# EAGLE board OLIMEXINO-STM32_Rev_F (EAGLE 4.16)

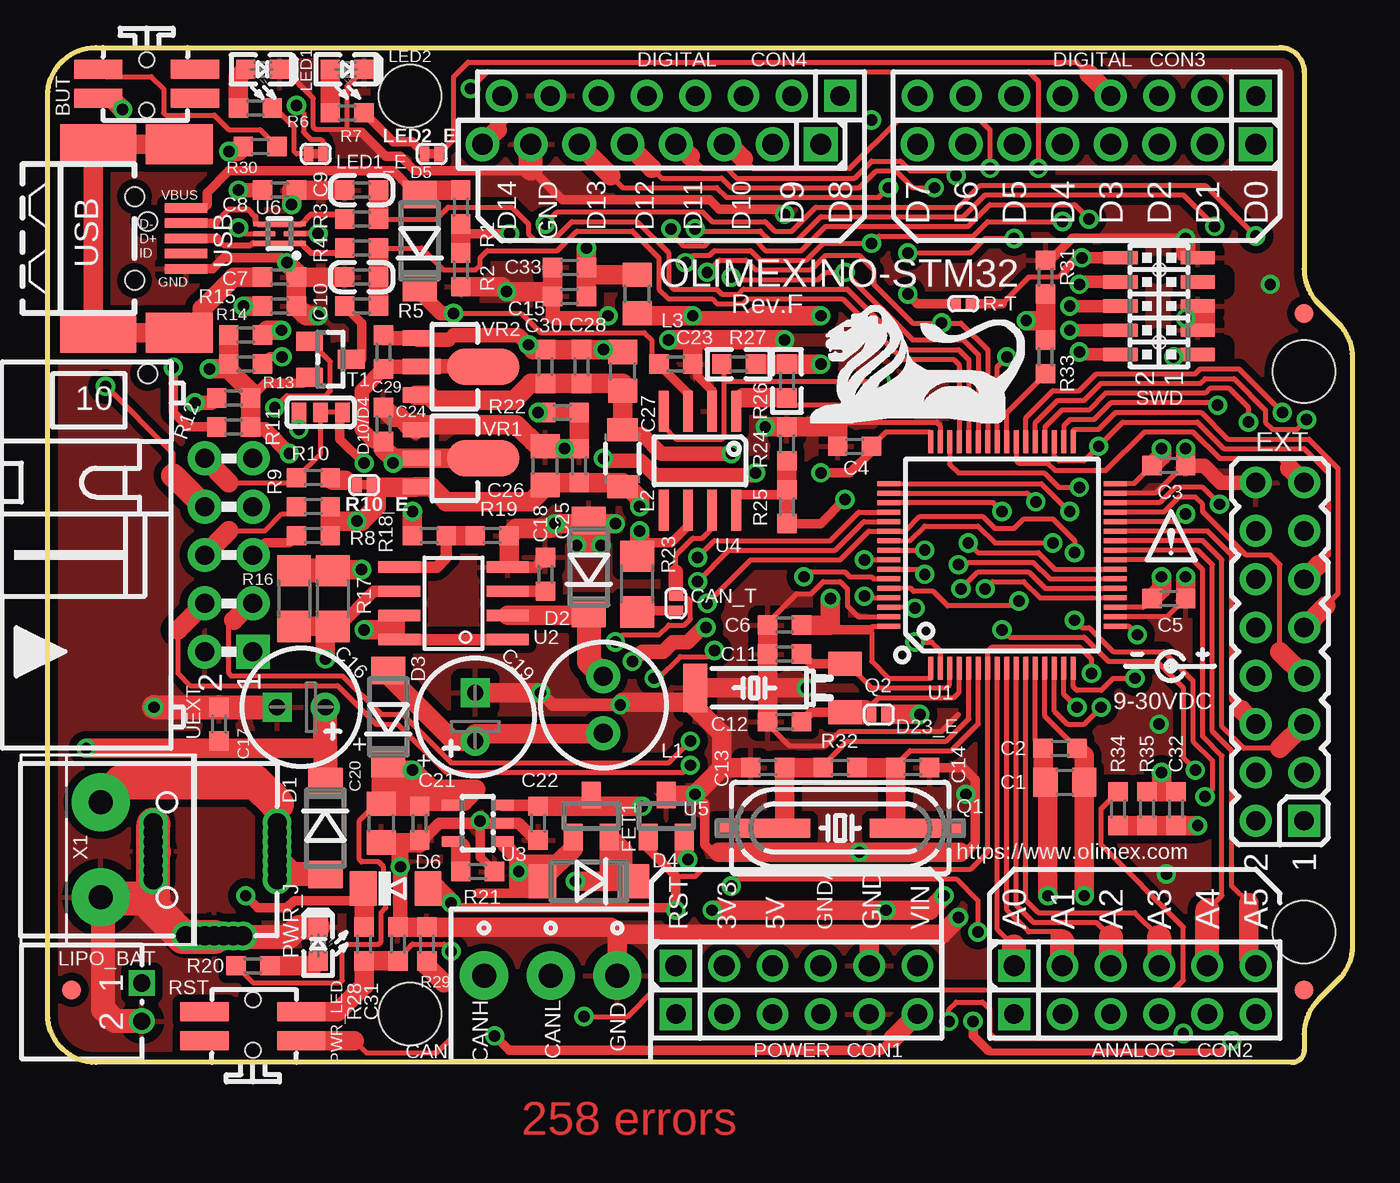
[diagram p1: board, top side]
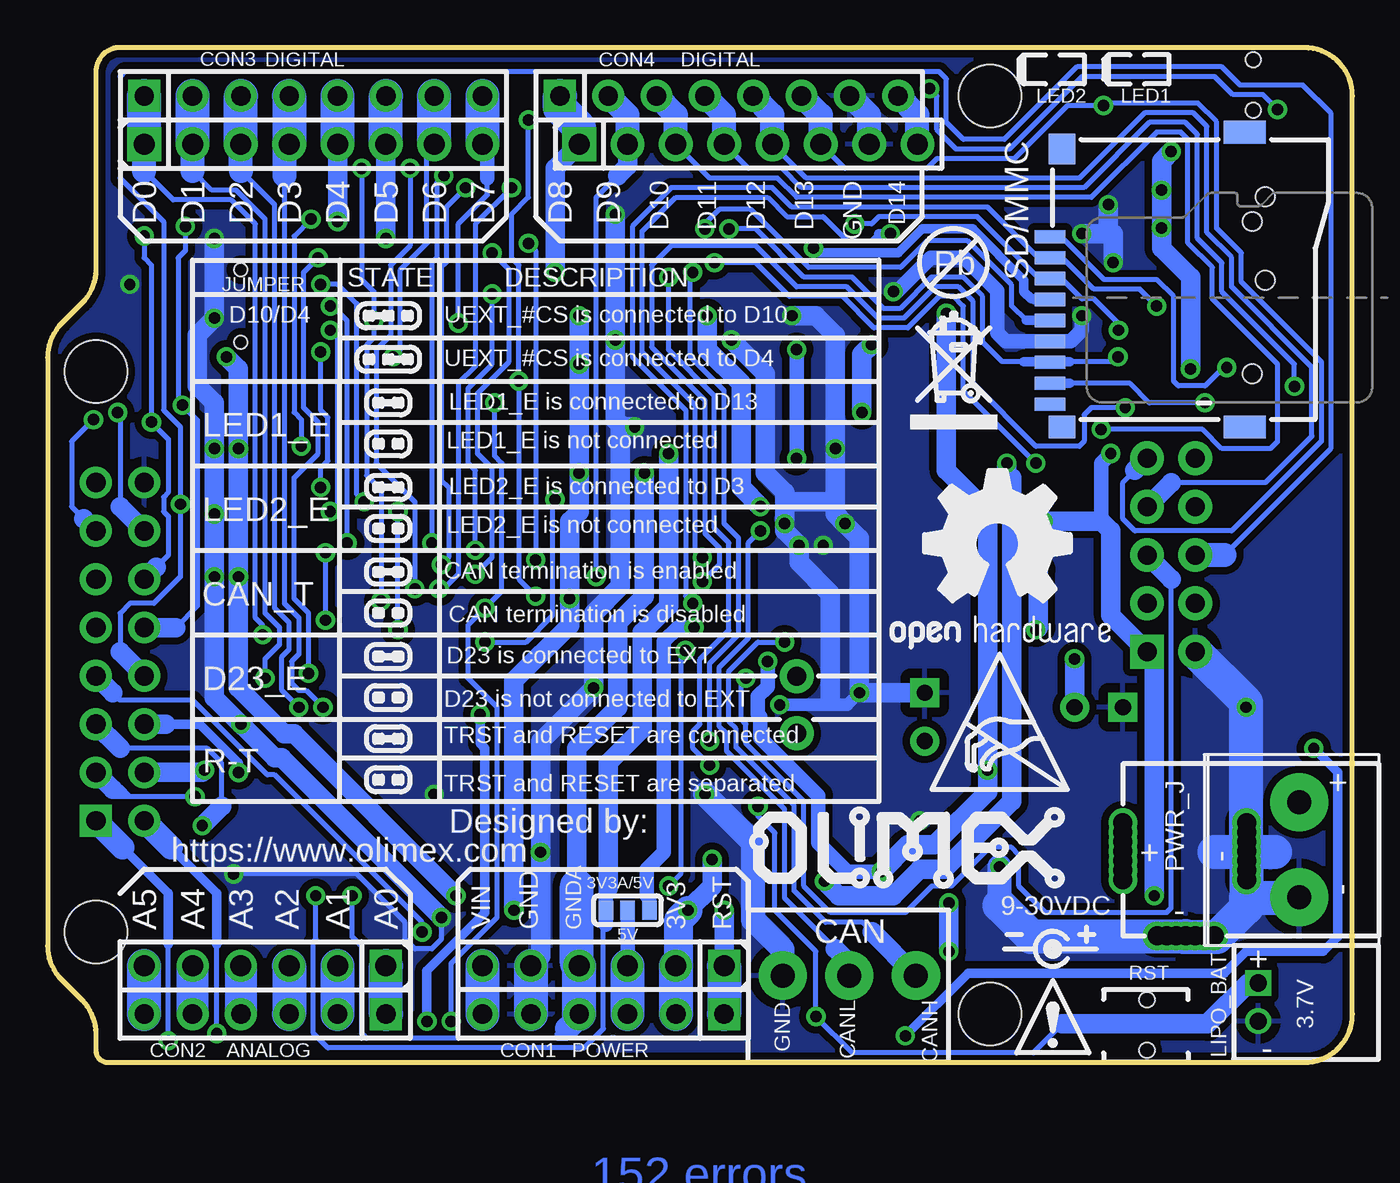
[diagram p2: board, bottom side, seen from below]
Size 68.58 x 53.34 mm. Coordinates in mm from the lower left corner, seen from the top.
Copper layers (1+16): Top 0.035mm / dielectric 1.5mm / Bottom 0.035mm
Design rules "default": minimum track width 10mil, minimum drill 0.6mm, track to track 9.5mil, track to pad 9.5mil, pad to pad 9.5mil, via to via 9.5mil, smd to smd 1mil, copper to edge 10mil, drill to drill 8mil, minimum pad ring 8mil, minimum via ring 8mil, stop-mask expansion 4mil, vias tented up to drill 25mil, thermal gap 20mil
Net classes: 0 default: width 0.241 mm, drill 0.241 mm, clearance 0.584 mm; 1 pwr: width 0.25 mm
tRestrict: 2 lines

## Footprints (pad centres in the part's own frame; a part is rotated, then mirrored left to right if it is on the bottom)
SJ_2_SMALL = smd 0.762 x 1.016: 1 -1.143,0; 2 0,0; 3 1.143,0
SW_TAKT3X4 = smd 2.54 x 1.016: 1_1 2.54,-0.762; 1_2 -2.54,-0.762; 2_1 2.54,0.762; 2_2 -2.54,0.762 | hole 0.8: 0,1.397; 0,-1.27
C0805_5MIL_DWS = smd 1.27 x 1.524: 1 -1.016,0; 2 1.016,0
C0603_DWS = smd 1.016 x 1.016: 1 -0.889,0; 2 0.889,0
C0603_DWS_NA = smd 1.016 x 1.016: 1 -0.889,0; 2 0.889,0
E2,5-6,3 = drill 0.864 pad 1.524 round: + -1.27,0 | drill 0.864 pad 1.524 square: - 1.27,0
CON3/3.5MM = drill 1.27 pad 2.54 round: 1 -1.75,-0.5; 2 1.75,-0.5; 3 5.25,-0.5
SJ_1_SMALLER = smd 0.508 x 0.762: 1 -0.381,0; 2 0.381,0
PN1X6 = drill 1.1 pad 1.676 square: 1 -6.35,0 | drill 1.1 pad 1.676 round: 2 -3.81,0; 3 -1.27,0; 4 1.27,0; 5 3.81,0; 6 6.35,0
PN1X8 = drill 1.1 pad 1.778 square: 1 -8.89,0 | drill 1.1 pad 1.778 round: 2 -6.35,0; 3 -3.81,0; 4 -1.27,0; 5 1.27,0; 6 3.81,0; 7 6.35,0; 8 8.89,0
MLL-41 = smd 1.45 x 1.8: A 2.445,0; K -2.445,0
MINI-MELF = smd 1.4 x 1.8: A 1.7,0; C -1.7,0
HN2X8-MALE = drill 1.016 pad 1.676 square: 1 -8.89,-1.27 | drill 1.016 pad 1.676 round: 2 -8.89,1.27; 3 -6.35,-1.27; 4 -6.35,1.27; 5 -3.81,-1.27; 6 -3.81,1.27; 7 -1.27,-1.27; 8 -1.27,1.27; 9 1.27,-1.27; 10 1.27,1.27; 11 3.81,-1.27; 12 3.81,1.27; 13 6.35,-1.27; 14 6.35,1.27; 15 8.89,-1.27; 16 8.89,1.27
SOT23 = smd 1.4 x 1: 1 1.1,-0.95; 2 1.1,0.95; 3 -1.1,0
SW68 = drill 1 pad 1.778 round: 1 -1.5,0; 2 1.5,0
L3216C = smd 1.2 x 1.6: 1 -1.5,0; 2 1.5,0
L0805_5MIL_DWS = smd 1.27 x 1.524: 1 -1.016,0; 2 1.016,0
LED-0603 = smd 1.016 x 1.016: A 0.889,0; C -0.889,0
SJ_1_SMALLER_CLOSE = smd 0.508 x 0.762: 1 -0.381,0; 2 0.381,0
DW02R = drill 0.9 square: 1 -1,0 | drill 0.9 round: 2 1,0
PWR_JACK_UNI_MILLING = drill 1 round: + 0,4.75; +1 0,5.25; +2 0,5.75; +3 0,6.25; +4 0,4.25; +5 0,3.75; +6 0,3.25; - -6.5,4.75; -1 -6.5,5.25; -2 -6.5,5.75; -3 -6.5,4.25; -4 -6.5,3.75; -5 -6.5,6.25; -6 -6.5,3.25; -- -3.3,0.3; --1 -3.8,0.3; --2 -4.3,0.3; --3 -4.8,0.3; --4 -2.8,0.3; --5 -2.3,0.3; --6 -1.8,0.3
HC49/SMD2_THIN = smd 5 x 1: 1 -4.064,0; 2 4.064,0
TC26H_3_REPAIR_SMD = smd 1.27 x 1.778: 1 -1.27,0; 2 1.27,0 | smd 2.54 x 1.27: GND 0,7.874
R0603_5MIL_DWS = smd 1.016 x 1.016: 1 -0.889,0; 2 0.889,0
R1206_5MIL_WS = smd 1.651 x 1.778: 1 -1.46,0; 2 1.46,0
0603_0R = smd 1.016 x 1.016: 1 -0.889,0; 2 0.889,0
R0603_5MIL_DWS_NA = smd 1.016 x 1.016: 1 -0.889,0; 2 0.889,0
SJ_1_THE_SMALLEST = smd 0.508 x 0.508: 1 -0.381,0; 2 0.381,0
TFC-WPAPR-08 = smd 1.6 x 0.7: 1 -7.375,2.25; 2 -7.375,1.15; 3 -7.375,0.05; 4 -7.375,-1.05; 5 -7.375,-2.15; 6 -7.375,-3.25; 7 -7.375,-4.35; 8 -7.375,-5.45; 9 -7.375,-6.55 | smd 1.4 x 1.2: 10 -6.75,-7.75 | smd 1.4 x 1.6: 11 -6.75,6.85 | smd 2.2 x 1.2: 12 2.85,-7.75; 13 2.85,7.75 | hole 1: 3.25,-4.95; 3.25,3.05
GPH127SMT-02X05(PA-V16X-2X5-LF) = smd 0.7 x 1.8: 1 -2.54,-2.032; 2 -2.54,2.032; 3 -1.27,-2.032; 4 -1.27,2.032; 5 0,-2.032; 6 0,2.032; 7 1.27,-2.032; 8 1.27,2.032; 9 2.54,-2.032; 10 2.54,2.032 | hole 0.7: -1.905,0; 1.905,0
SOT-23 = smd 1.4 x 1: 1 1.1,-0.95; 2 1.1,0.95; 3 -1.1,0
LPTQFP64 = smd 0.254 x 1.2: 1 -3.75,-5.95; 2 -3.25,-5.95; 3 -2.75,-5.95; 4 -2.25,-5.95; 5 -1.75,-5.95; 6 -1.25,-5.95; 7 -0.75,-5.95; 8 -0.25,-5.95; 9 0.25,-5.95; 10 0.75,-5.95; 11 1.25,-5.95; 12 1.75,-5.95; 13 2.25,-5.95; 14 2.75,-5.95; 15 3.25,-5.95; 16 3.75,-5.95; 33 3.75,5.95; 34 3.25,5.95; 35 2.75,5.95; 36 2.25,5.95; 37 1.75,5.95; 38 1.25,5.95; 39 0.75,5.95; 40 0.25,5.95; 41 -0.25,5.95; 42 -0.75,5.95; 43 -1.25,5.95; 44 -1.75,5.95; 45 -2.25,5.95; 46 -2.75,5.95; 47 -3.25,5.95; 48 -3.75,5.95 | smd 1.2 x 0.254: 17 5.95,-3.75; 18 5.95,-3.25; 19 5.95,-2.75; 20 5.95,-2.25; 21 5.95,-1.75; 22 5.95,-1.25; 23 5.95,-0.75; 24 5.95,-0.25; 25 5.95,0.25; 26 5.95,0.75; 27 5.95,1.25; 28 5.95,1.75; 29 5.95,2.25; 30 5.95,2.75; 31 5.95,3.25; 32 5.95,3.75; 49 -5.95,3.75; 50 -5.95,3.25; 51 -5.95,2.75; 52 -5.95,2.25; 53 -5.95,1.75; 54 -5.95,1.25; 55 -5.95,0.75; 56 -5.95,0.25; 57 -5.95,-0.25; 58 -5.95,-0.75; 59 -5.95,-1.25; 60 -5.95,-1.75; 61 -5.95,-2.25; 62 -5.95,-2.75; 63 -5.95,-3.25; 64 -5.95,-3.75
SO-8 = smd 0.6 x 2.2: 1 -1.905,-2.854; 2 -0.635,-2.854; 3 0.635,-2.854; 4 1.905,-2.854; 5 1.905,2.854; 6 0.635,2.854; 7 -0.635,2.854; 8 -1.905,2.854
SOT-23-5 = smd 1.2 x 0.55: 1 1.3,-0.95; 2 1.3,0; 3 1.3,0.95; 4 -1.3,0.95; 5 -1.3,-0.95
SO-08_THIN = smd 0.508 x 2.159: 1 -1.905,-2.603; 2 -0.635,-2.603; 3 0.635,-2.603; 4 1.905,-2.603; 5 1.905,2.603; 6 0.635,2.603; 7 -0.635,2.603; 8 -1.905,2.603
USBLC6-2P6 = smd 1.46 x 0.25: 1 0.65,-0.5; 3 0.65,0.5; 4 -0.65,0.5; 6 -0.65,-0.5 | smd 1.16 x 0.25: 2 0.8,0; 5 -0.8,0
FIDUCIAL-1X2 = smd 1 x 1: 1 0,0
STM32-MAPLE_PATFORM-CON1-PIN3_5V = drill 1.016 pad 1.676 round: 3V3 35.56,2.54; 5V 38.1,2.54; A1 53.34,2.54; A2 55.88,2.54; A3 58.42,2.54; A4 60.96,2.54; A5 63.5,2.54; D1 60.96,50.8; D2 58.42,50.8; D3 55.88,50.8; D4 53.34,50.8; D5 50.8,50.8; D6 48.26,50.8; D7 45.72,50.8; D9 39.116,50.8; D10 36.576,50.8; D11 34.036,50.8; D12 31.496,50.8; D13 28.956,50.8; D14 23.876,50.8; GND 43.18,2.54; GND@1 26.416,50.8; GNDA 40.64,2.54; VIN 45.72,2.54 | drill 1.016 pad 1.676 square: A0 50.8,2.54; D0 63.5,50.8; D8 41.656,50.8; RST 33.02,2.54 | hole 3.3: 66.04,36.322; 66.04,6.858; 19.05,50.8; 19.05,2.54
BH10R = drill 1 pad 1.778 square: 1 -5.08,-1.27 | drill 1 pad 1.778 round: 2 -5.08,1.27; 3 -2.54,-1.27; 4 -2.54,1.27; 5 0,-1.27; 6 0,1.27; 7 2.54,-1.27; 8 2.54,1.27; 9 5.08,-1.27; 10 5.08,1.27
USB_MINI_9PIN-SMALLER_CREAM = smd 2.25 x 0.5: D+ -5.246,0; D- -5.246,-0.8; GND -5.246,1.6; ID -5.246,0.8; VBUS -5.246,-1.6 | smd 4 x 2.1: GND1 -0.64,-4.95; GND3 -0.64,4.95 | smd 3.5 x 2.1: GND2 -4.89,-4.95; GND4 -4.89,4.95 | hole 1: -2.54,-2.2; -2.54,2.2
SOT89_REP_THERMALOFF = smd 1.4 x 0.8: 1 1.981,-1.499; 3 1.981,1.499 | smd 2 x 0.8: 2 1.681,0 | smd 3.81 x 1.93: P$2 -1.57,0
W237-102 = drill 1.27 pad 3.048 round: 1 -2.5,-1.27; 2 2.5,-1.27

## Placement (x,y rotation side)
3V3A/5V  5V_default  [SJ_2_SMALL]  38.1,8 0 bottom
BUT  SW-SIDE_WTCM-TR(3X4)  [SW_TAKT3X4]  5.21,51.44 180 top
C1  10uF/6.3V  [C0805_5MIL_DWS]  53.47,14.73 0 top
C2  100nF  [C0603_DWS]  53.21,16.51 0 top
C3  100nF  [C0603_DWS]  58.93,31.37 180 top
C4  100nF  [C0603_DWS]  42.42,32.38 0 top
C5  100nF  [C0603_DWS]  58.93,24.38 180 top
C6  4.7uF/6.3V  [C0603_DWS]  38.73,22.99 0 top
C7  10nF  [C0603_DWS]  12.19,41.27 0 top
C8  100nF  [C0603_DWS]  12.19,45.85 180 top
C9  NA(47pF)  [C0603_DWS_NA]  16.51,45.85 180 top
C10  NA(47pF)  [C0603_DWS_NA]  16.51,41.27 180 top
C11  10pF  [C0603_DWS]  38.73,21.46 180 top
C12  10pF  [C0603_DWS]  38.73,17.91 180 top
C13  27pF  [C0603_DWS]  37.85,15.49 180 top
C14  27pF  [C0603_DWS]  45.47,15.49 0 top
C15  22uF/6.3V  [C0603_DWS]  27.43,40.26 180 top
C16  CE 100uF/35V/6.3x11mm/RM2.5  [E2,5-6,3]  13.34,18.67 180 top
C17  100nF  [C0603_DWS]  9.02,17.78 90 top
C18  820pF  [C0603_DWS]  26.16,25.65 90 top
C19  CE 470uF/10V/6.3x11mm/RM2.5  [E2,5-6,3]  22.48,18.16 90 top
C20  10uF/6.3V  [C0805_5MIL_DWS]  17.53,12.57 270 top
C21  2.2uF  [C0603_DWS]  19.56,12.57 270 top
C22  2.2uF  [C0603_DWS]  25.78,12.57 270 top
C23  100nF  [C0603_DWS]  33.02,36.7 0 top
C24  2.2uF  [C0603_DWS]  17.65,33.53 90 top
C25  100nF  [C0603_DWS]  27.94,31.37 90 top
C26  10uF/6.3V  [C0805_5MIL_DWS]  26.16,31.37 90 top
C27  10uF/6.3V  [C0805_5MIL_DWS]  30.23,36.32 90 top
C28  10nF  [C0603_DWS]  28.07,36.58 90 top
C29  2.2uF  [C0603_DWS]  17.65,37.34 90 top
C30  2.2uF  [C0603_DWS]  26.16,36.58 90 top
C31  100nF  [C0603_DWS]  18.41,6.22 90 top
C32  10nF  [C0603_DWS]  59.31,13.34 270 top
C33  22uF/6.3V  [C0603_DWS]  27.43,41.78 180 top
CAN  TB3-3.5MM  [CON3/3.5MM]  28.19,4.06 180 top
CAN_T  Open  [SJ_1_SMALLER]  33.02,24.13 90 top
CON1  NA  [PN1X6]  39.37,5.08 0 top
CON2  NA  [PN1X6]  57.15,5.08 0 top
CON3  NA  [PN1X8]  54.61,48.26 180 top
CON4  NA  [PN1X8]  31.75,48.26 180 top
D1  1N5819S/SS14  [MLL-41]  14.61,12.32 270 top
D2  1N5819S/SS14  [MLL-41]  28.45,26.04 90 top
D3  1N5819S/SS14  [MLL-41]  17.91,18.16 90 top
D4  1N5819S/SS14  [MLL-41]  28.45,9.53 180 top
D5  1N5819S/SS14  [MLL-41]  19.56,43.18 90 top
D6  1N4148/mini-melf  [MINI-MELF]  18.29,9.14 0 top
D10/D4  D10:Open/D4:Close  [SJ_2_SMALL]  14.35,34.16 180 top
D23_E  Open  [SJ_1_SMALLER]  43.69,18.29 0 top
EXT  PN2x8  [HN2X8-MALE]  64.77,21.59 90 top
FET1  IRLML6402  [SOT23]  28.57,12.95 270 top
L1  CL10uH SW68  [SW68]  29.21,18.8 270 top
L2  NA  [L3216C]  30.23,31.75 90 top
L3  CL470nH/0805/1.76R/250mA  [L0805_5MIL_DWS]  30.99,40.39 90 top
LED1  GREEN(0603)  [LED-0603]  11.3,52.2 180 top
LED1_E  Close  [SJ_1_SMALLER_CLOSE]  14.1,47.75 0 top
LED2  YELLOW(0603)  [LED-0603]  15.75,52.2 180 top
LED2_E  Close  [SJ_1_SMALLER_CLOSE]  20.19,47.75 0 top
LIPO_BAT  DW02R  [DW02R]  4.95,3.17 270 top
PWR_J  YDJ-1136  [PWR_JACK_UNI_MILLING]  12.06,6.35 0 top
PWR_LED  RED(0603)  [LED-0603]  14.22,6.22 270 top
Q1  HC49/S1  [HC49/SMD2_THIN]  41.66,12.32 180 top
Q2  32768Hz/6pF  [TC26H_3_REPAIR_SMD]  41.91,19.68 90 top
R1  15k  [R0603_5MIL_DWS]  21.72,44.96 270 top
R2  22k  [R0603_5MIL_DWS]  21.72,41.66 270 top
R3  22R  [R0603_5MIL_DWS]  16.51,44.32 180 top
R4  22R  [R0603_5MIL_DWS]  16.51,42.8 180 top
R5  1.5k  [R0603_5MIL_DWS]  16.51,39.75 180 top
R6  2k  [R0603_5MIL_DWS]  10.92,50.16 0 top
R7  2k  [R0603_5MIL_DWS]  15.75,49.91 0 top
R8  4.7k  [R0603_5MIL_DWS]  13.97,27.69 0 top
R9  4.7k  [R0603_5MIL_DWS]  13.97,29.21 0 top
R10  10k  [R0603_5MIL_DWS]  13.97,30.73 0 top
R10_E  Close  [SJ_1_SMALLER_CLOSE]  16.64,30.35 0 top
R11  100k  [R0603_5MIL_DWS]  9.78,33.4 180 top
R12  100k  [R0603_5MIL_DWS]  9.78,34.92 180 top
R13  100k  [R0603_5MIL_DWS]  10.41,36.7 0 top
R14  10k  [R0603_5MIL_DWS]  10.41,38.23 0 top
R15  1M  [R0603_5MIL_DWS]  12.19,39.75 180 top
R16  0.47R  [R1206_5MIL_WS]  12.95,24.38 90 top
R17  0.47R  [R1206_5MIL_WS]  14.99,24.38 90 top
R18  3.01k/1%  [R0603_5MIL_DWS]  20.07,27.69 0 top
R19  1k/1%  [R0603_5MIL_DWS]  23.37,27.69 0 top
R20  2k  [R0603_5MIL_DWS]  10.79,5.08 0 top
R21  15k  [R0603_5MIL_DWS]  22.61,10.03 180 top
R22  0R(boad mounted)  [0603_0R]  27.05,34.16 180 top
R23  120R  [R1206_5MIL_WS]  30.99,25.15 270 top
R24  10k  [R0603_5MIL_DWS]  38.86,32.51 270 top
R25  0R(boad mounted)  [0603_0R]  38.86,29.21 90 top
R26  NA(4.7k)  [R0603_5MIL_DWS_NA]  38.86,35.81 270 top
R27  NA(4.7k)  [R0603_5MIL_DWS_NA]  36.32,36.7 180 top
R28  10k  [R0603_5MIL_DWS]  16.64,6.22 270 top
R29  330R  [R0603_5MIL_DWS]  19.94,6.22 270 top
R30  1k  [R0603_5MIL_DWS]  11.18,48.13 0 top
R31  10k  [R0603_5MIL_DWS]  52.45,41.27 90 top
R32  1M  [R0603_5MIL_DWS]  41.66,15.49 180 top
R33  1k  [R0603_5MIL_DWS]  52.45,37.08 270 top
R34  3M  [R0603_5MIL_DWS]  56.26,13.34 90 top
R35  1M  [R0603_5MIL_DWS]  57.78,13.34 90 top
R-T  Open  [SJ_1_THE_SMALLEST]  48.13,39.88 0 top
RST  SW-SIDE_WTCM-TR(3X4)  [SW_TAKT3X4]  10.79,1.91 0 top
SD/MMC  MICRO_SD/TFC-WPAPR-08  [TFC-WPAPR-08]  8.51,41.15 0 bottom
SWD  GPH127SMT-02x05(PIN7-CUT)  [GPH127SMT-02X05(PA-V16X-2X5-LF)]  58.42,39.75 90 top
T1  DTA114YKA  [SOT-23]  14.86,36.96 180 top
U1  STM32F103RBT6(LQFP64)  [LPTQFP64]  50.16,26.67 0 top
U2  MC33063ADR(SO8)  [SO-8]  21.34,24.13 90 top
U3  MCP73812T-420I/OT  [SOT-23-5]  22.61,12.57 0 top
U4  MCP2551-I/SN  [SO-08_THIN]  34.29,31.62 180 top
U5  NA  [SOT23]  32.51,12.95 270 top
U6  NA  [USBLC6-2P6]  12.19,43.56 0 top
U$1  [LION_12X7MM]  45.34,35.18 0 top
U$2  FIDUCIAL1X2  [FIDUCIAL-1X2]  1.27,3.81 90 top
U$3  FIDUCIAL1X2  [FIDUCIAL-1X2]  66.04,3.81 90 top
U$4  FIDUCIAL1X2  [FIDUCIAL-1X2]  66.04,39.37 90 top
U$5  [PB_SMALL]  20.95,42.04 0 bottom
U$6  [RECYCLE_BIN1/8]  23.24,33.27 0 bottom
U$7  [ESD_SYMBOL]  22.1,14.35 0 bottom
U$8  [ATTENTION_SMALL]  57.78,26.4 0 top
U$9  [OLIMEX1_V]  13.97,9.02 0 bottom
U$10  [ROHS]  not placed on the board
U$11  [LOGO-OPENHARDWARE_8X8]  18.67,27.18 0 bottom
U$12  [ATTENTION]  17.65,0.51 0 bottom
U$13  STM32-MAPLE_PLATFORM-CON1-PIN3-5V  [STM32-MAPLE_PATFORM-CON1-PIN3_5V]  0,0 0 top
UEXT  BH10R  [BH10R]  9.53,26.67 90 top
USB  MINI_USB9SMALLER_CREAM  [USB_MINI_9PIN-SMALLER_CREAM]  2.03,43.31 180 top
VR1  MCP1700T-3302E/MB  [SOT89_REP_THERMALOFF]  21.34,31.75 180 top
VR2  MCP1700T-3302E/MB  [SOT89_REP_THERMALOFF]  21.34,36.58 180 top
X1  NA  [W237-102]  4.06,11.18 270 top

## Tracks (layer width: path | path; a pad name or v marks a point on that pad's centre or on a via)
+5V  (via drill 0.6)
  Top 0.254: R20.1 10.79,4.19 15.37,4.19 15.49,4.32 15.49,5.97 15.75,6.22 17.4,6.22 17.53,6.35 17.53,7.87 17.78,8.13 17.78,9.78 17.67,9.89 17.67,10.27 17.4,10.54 16.51,10.54 16.38,10.67 16.38,12.7 17.27,13.59 C20.1 | C23.1 31.75,37.08 31.75,37.97 31.37,38.35 25.91,38.35 24.89,39.37 v21.34,39.37
  Top 0.508: U4.3 33.66,35.18 C23.1 | 22.61,8.89 24.86,8.89 24.86,9.14
  Top 0.559: U3.1 23.91,11.53 24,11.43
  Top 0.61: U3.4 19.56,13.52 C21.1
  Top 0.762: v24.77,10.03 24.64,10.03 24.64,10.54 | 24,11.43 24.64,10.79 24.64,10.54 | v21.34,39.37 20.67,39.37 19.56,40.48 D5.K | 24.64,10.54 26.92,10.54 | v30.73,21.08 31.24,21.59 32.36,21.59 32.87,22.1 33.66,22.1 34.42,22.86 v34.61,22.86
  Top 1.016: v19.18,28.96 R18.1 | 17.91,15.37 D3.K 17.91,15.49 | 17.91,15.37 v19.18,15.37 20.32,14.22 | 17.53,13.72 C20.1 17.53,13.46 C21.1 19.56,13.72 17.53,13.72 | FET1.1 27.62,11.24 26.92,10.54 26.04,9.65 26.04,9.53 D4.A 26,10.03 v24.77,10.03 24.77,9.14 24.86,9.14 26,9.14 | 17.53,13.72 21.87,13.72 22.5,14.35 17.91,14.35 17.91,15.37 | 17.53,13.72 17.53,15.49 17.91,15.49 | 17.91,15.49 17.91,15.37
  Bottom 0.762: v24.77,10.03 26.54,10.03 28.07,11.56 28.07,14.02 31.11,17.07 31.11,18.16 31.24,18.29 31.24,19.24 30.73,19.75 v30.73,21.08 | v34.61,22.86 35.47,22.86 36.2,22.14 36.2,11.05 37.08,10.16 37.08,8.76 36.96,8.64 3V3A/5V.3
  Bottom 1.016: v24.77,10.03 23.37,11.43 21.97,11.43 19.18,14.22 v19.18,15.37 v19.18,28.96 21.34,31.11 v21.34,39.37
+5V_USB
  Top 0.508: USB.VBUS 8.2,44.91 8.38,45.09 8.38,45.72 9.53,46.86 18.16,46.86 19.3,45.72 19.56,45.72
  Top 0.762: 19.56,45.72 19.56,45.85
  Top 1.016: D5.A 19.56,45.85 R1.1
+24V  (via drill 0.6)
  Top 0.508: v23.5,1.4 24.26,0.64 43.81,0.64 44.45,1.27
  Top 0.61: U2.6 17.14,24.77 15.24,22.86 15.24,22.73
  Top 1.016: R17.1 14.99,22.73 | v14.61,21.21 14.61,22.73 15.24,22.73 15.24,22.67 R17.1 | R17.1 R16.1 | v2.03,16.51 9.02,16.51 | 9.02,16.51 14.61,16.51 | 44.45,1.27 U$13.VIN | 9.02,16.51 C17.1
  Top 1.27: D1.K 14.61,16.51 C16.+
  Bottom 0.508: v2.03,16.51 0.76,15.24 0.76,6.6 1.52,5.84 5.59,5.84 6.73,4.7 20.19,4.7 v23.5,1.4
  Bottom 1.016: C16.+ v14.61,21.21
  Bottom 1.778: U$13.VIN CON1.6
AGND  (via drill 0.6)
  Top 0.254: U1.12 51.91,16.92 C2.1
  Top 0.762: v37.21,30.99 37.21,30.86 31.93,30.86 31.17,31.62 29.21,31.62 v29.21,31.75 | C29.2 17.65,38.08 VR2.1 19.46,37.97 21.08,37.97 21.34,38.23 24.77,38.23 v25.27,37.72 | R22.2 28.07,34.16
  Top 1.016: C2.1 52.32,14.73 C1.1 52.45,14.61 52.58,14.48 v52.58,8.76 | C27.2 30.23,37.47 v29.21,37.47 C28.2 C30.2 25.53,37.47 v25.27,37.72 | v25.78,34.16 R22.2
  Bottom 0.254: 41.27,1.78 41.27,1.27 41.78,1.27 | 41.78,1.27 51.82,1.27 52.07,1.52 52.07,6.1 52.58,6.6 v52.58,8.76 | 41.78,1.27 41.78,1.52
  Bottom 0.762: v29.21,31.75 v29.21,37.47
  Bottom 1.016: 40.77,9.27 40.77,16.51 38.61,18.67 38.61,23.11 37.21,24.51 v37.21,30.99 | v25.27,37.72 25.78,37.21 v25.78,34.16
  Bottom 1.27: 41.27,1.78 40.64,2.41 U$13.GNDA
  Bottom 1.778: U$13.GNDA CON1.4 40.77,5.21 40.77,9.27
BOOT0  (via drill 0.6)
  Top 0.254: U1.60 45.37,24.92 45.52,24.77 46.54,24.77 47.3,24 50.8,24 v51.05,24.26 | v52.07,46.99 52.07,51.56 51.56,52.07 23.11,52.07 v22.23,51.18
  Top 1.016: 52.45,38.99 R33.1 | BUT.2_1 3.35,50.67 v3.94,50.09 | v51.44,38.99 52.45,38.99 | 52.45,38.99 R31.1
  Bottom 0.254: v51.05,24.26 51.05,30.1 51.82,30.86 51.82,37.72 51.44,38.1 v51.44,38.99 51.44,40.51 52.07,41.15 v52.07,46.99 | v3.94,50.09 4.71,50.86 6.29,50.86 7.24,51.82 14.22,51.82 18.03,48.01 20.83,48.01 21.84,49.02 21.84,50.8 v22.23,51.18
D0(RXD2)  (via drill 0.6)
  Top 0.254: U1.17 56.84,22.92 v57.28,22.48
  Bottom 0.254: v57.28,22.48 57.28,22.99 57.66,23.37 57.66,44.07 58.93,45.34 61.98,45.34 63.5,46.86
  Bottom 1.27: 63.5,46.86 CON3.1
  Bottom 1.778: CON3.1 U$13.D0
D1(TXD2)  (via drill 0.6)
  Top 0.254: U1.16 53.91,19.75 54.1,19.56 55.37,19.56 56.01,20.19 v57.15,20.19
  Bottom 0.254: v57.15,20.19 57.15,21.21 56.39,21.97 56.39,22.86 57.15,23.62 57.15,44.32 58.67,45.85 59.94,45.85 60.96,46.86
  Bottom 1.27: 60.96,46.86 CON3.2
  Bottom 1.778: CON3.2 U$13.D1
D2  (via drill 0.6)
  Top 0.254: U1.14 52.91,18.46 53.59,17.78 54.48,17.78 v55.37,18.67
  Bottom 0.254: v55.37,18.67 56.26,19.56 56.26,21.34 55.88,21.72 55.88,23.11 56.64,23.88 56.64,45.09 58.42,46.86
  Bottom 1.27: 58.42,46.86 CON3.3
  Bottom 1.778: CON3.3 U$13.D2
D3(LED2)  (via drill 0.6)
  Top 0.254: U1.15 53.41,19.36 v54.1,18.67 | LED2_E.2 21.34,48.51 21.34,51.82 22.1,52.58 54.1,52.58 54.74,51.94
  Top 1.016: 54.74,51.94 U$13.D3
  Bottom 0.254: v54.1,18.67 54.99,19.56 55.37,19.56 55.75,19.94 55.75,21.08 55.37,21.46 55.37,23.37 56.13,24.13 56.13,46.61
  Bottom 1.27: 56.13,46.61 56.13,48.01 CON3.4
  Bottom 1.778: U$13.D3 CON3.4
D4  (via drill 0.6)
  Top 0.254: v42.93,26.42 U1.57 | v53.34,44.2 49.4,44.2 48.64,43.43 43.69,43.43 v43.31,43.05 40.77,43.05 39.88,42.16 37.47,42.16 36.96,42.67 35.05,42.67 34.8,42.42 33.91,42.42 v33.53,42.04 | 15.37,34.16 14.35,34.16
  Top 0.508: v16.64,31.5 15.37,32.77 15.37,34.16 D10/D4.1
  Bottom 0.254: v42.93,26.42 42.93,42.67 v43.31,43.05 | v16.64,31.5 20.45,35.31 20.45,39.75 20.95,40.26 21.72,40.26 23.37,38.61 25.15,38.61 26.8,40.26 29.59,40.26 31.37,42.04 v33.53,42.04
  Bottom 1.016: v53.34,44.2 CON3.5
  Bottom 1.778: CON3.5 U$13.D4
D5  (via drill 0.6)
  Top 0.254: U1.58 45.84,25.92 v46.1,25.65 | v45.21,42.55 48.51,42.55 49.28,43.31 v50.8,43.31
  Bottom 0.254: v46.1,25.65 45.21,26.54 45.21,31.24 45.97,32 45.97,35.18 44.32,36.83 44.32,41.66 v45.21,42.55
  Bottom 1.016: v50.8,43.31 CON3.6
  Bottom 1.778: CON3.6 U$13.D5
D6  (via drill 0.6)
  Top 0.254: U1.41 49.91,36.57 v50.42,37.08
  Bottom 0.254: v50.42,37.08 50.04,37.47 50.04,41.66 48.64,43.05 48.64,47.88 CON3.7
  Bottom 1.778: CON3.7 U$13.D6
D7(TXD1)  (via drill 0.6)
  Top 0.254: U1.42 49.41,37.45 48.01,38.86 v46.99,38.86 45.47,38.86 43.43,40.89 43.43,41.66 42.67,42.42 40.89,42.42 40.13,41.66 37.21,41.66 36.7,42.16 35.31,42.16 v34.67,41.53 | v33.78,16.89 32.64,15.75 21.21,15.75 18.67,18.29 17.53,18.29 15.49,20.32 9.65,20.32 9.53,20.45 9.53,22.99 9.78,23.24
  Top 1.016: 9.78,23.24 10.67,24.13 UEXT.3
  Bottom 0.254: v46.99,38.86 46.99,44.07 45.47,45.59 45.47,46.48 | v34.67,41.53 34.8,41.4 34.8,37.08 33.02,35.31 33.02,28.32 32.26,27.56 32.26,22.5 33.78,20.98 v33.78,16.89
  Bottom 0.508: 45.47,48.01 CON3.8
  Bottom 0.762: 45.47,46.48 45.47,48.01
  Bottom 1.778: CON3.8 U$13.D7
D8(RXD1)  (via drill 0.6)
  Top 0.254: U1.43 48.91,37.19 48.13,37.97 45.47,37.97 v41.91,41.53 40.89,41.53 40.51,41.15 36.07,41.15 v35.94,41.27 | v33.78,15.62 33.4,15.24 20.95,15.24 18.41,17.78 17.27,17.78 15.24,19.81 7.49,19.81 6.86,20.45 6.86,22.73
  Top 1.016: 6.86,22.73 UEXT.4
  Bottom 0.254: v35.94,41.27 35.94,37.47 33.53,35.05 33.53,28.07 32.77,27.3 32.77,22.71 34.29,21.18 34.29,17.78 34.67,17.4 34.67,16.51 v33.78,15.62
  Bottom 1.016: v41.91,41.53 41.91,46.99 CON4.1
  Bottom 1.778: CON4.1 40.64,49.15 41.66,50.16 U$13.D8
D9  (via drill 0.6)
  Top 0.254: v39.75,25.53 40.01,25.78 41.91,25.78 42.17,25.52 43.31,25.52 43.41,25.42 U1.59
  Bottom 0.254: v39.75,25.53 39.75,45.47 38.61,46.61
  Bottom 1.016: 38.61,46.61 38.1,47.12 CON4.2
  Bottom 1.27: CON4.2 38.1,49.78 U$13.D9
D10(#SS1)  (via drill 0.6)
  Top 0.254: U1.20 52.16,24.42 51.31,25.27 49.66,25.27 v49.28,24.89 | v49.53,46.99 49.53,49.02 49.02,49.53 44.7,49.53 42.16,46.99 37.08,46.99 36.58,47.5
  Top 0.508: v13.21,33.27 D10/D4.3
  Top 1.016: CON4.3 35.81,48.26 36.58,47.5
  Bottom 0.254: v49.28,24.89 49.28,29.46 51.31,31.5 51.31,37.47 50.55,38.23 50.55,41.91 49.53,42.93 v49.53,46.99 | CON4.3 33.78,46.48 30.23,46.48 29.21,45.47 13.72,45.47 10.29,48.9 9.02,48.9 8.65,48.53 8.65,43.07 7.37,41.78 7.37,40.13 3.94,36.7 3.94,32.64 4.32,32.26 6.86,32.26 7.87,33.27 v13.21,33.27
  Bottom 1.27: CON4.3 35.56,49.78 U$13.D10
D11(MOSI1)  (via drill 0.6)
  Top 0.254: U1.23 52.95,25.92 52.07,26.8 48.9,26.8 v48.39,27.3 | v47.75,46.61 47.5,46.86 45.34,46.86 44.83,47.37 43.31,47.37 42.42,46.48 36.2,46.48 35.69,46.99 34.42,46.99 33.78,47.62 | v3.05,35.53 3.05,35.56 6.6,32 6.6,30.86
  Top 1.016: CON4.4 33.15,48.26 33.78,47.62
  Top 1.27: UEXT.8 6.6,30.86
  Bottom 0.254: v48.39,27.3 48.39,42.04 48.13,42.29 48.13,46.23 v47.75,46.61 | CON4.4 31.75,46.99 29.97,46.99 28.96,45.97 14.1,45.97 10.67,49.4 8.78,49.4 8.15,48.78 8.15,43.32 6.86,42.02 6.86,40.51 3.05,36.7 v3.05,35.53
  Bottom 1.27: CON4.4 33.02,49.78 U$13.D11
D12(MISO1)  (via drill 0.6)
  Top 0.254: U1.22 52.69,25.42 51.82,26.29 48.01,26.29 v47.88,26.16 | v46.61,45.97 45.47,45.97 44.58,46.86 43.56,46.86 42.67,45.97 35.94,45.97 35.43,46.48 32.26,46.48 31.75,46.99
  Top 1.016: CON4.5 31.75,46.99
  Bottom 0.254: v47.88,26.16 47.5,26.54 47.5,30.23 47.88,30.61 47.88,41.78 47.62,42.04 47.62,44.96 v46.61,45.97 | CON4.5 28.7,46.48 14.35,46.48 10.92,49.91 8.36,49.91 7.64,49.2 7.64,43.61 6.35,42.32 6.35,40.77 2.13,36.55 2.13,32.92 4.57,30.48 9.53,30.48
  Bottom 1.016: 9.53,30.48 UEXT.7
  Bottom 1.27: CON4.5 30.48,49.78 U$13.D12
D13(SCK1/LED1)  (via drill 0.6)
  Top 0.254: U1.21 52.42,24.92 51.56,25.78 48.9,25.78 v48.01,24.89 | v44.2,45.97 43.69,45.47 35.69,45.47 35.18,45.97 30.23,45.97 29.59,46.61 | v13.08,50.29 13.46,49.91 13.46,48.9 13.84,48.51 14.35,48.51 14.48,48.39 LED1_E.2
  Top 1.016: CON4.6 29.59,46.61
  Bottom 0.254: v48.01,24.89 47.75,24.89 46.99,25.65 46.99,35.69 46.1,36.58 46.1,44.07 v44.2,45.97 | CON4.6 26.67,46.99 22.35,46.99 21.84,47.5 17.78,47.5 14.99,50.29 v13.08,50.29 12.95,50.42 8.13,50.42 7.14,49.43 7.14,43.84 5.84,42.55 5.84,41.02 1.63,36.8 1.63,32.66 6.35,27.94 11.43,27.94 12.06,28.57 12.06,30.48 11.43,31.11
  Bottom 1.016: 11.43,31.11 UEXT.9
  Bottom 1.27: CON4.6 27.94,49.78 U$13.D13
D14(CANRX)  (via drill 0.6)
  Top 0.254: v42.93,24.51 43.02,24.42 U1.61 | 35.56,35.81 v43.81,35.81 | U4.4 32.38,33.4 33.02,32.77 35.43,32.77 35.56,32.89 35.56,35.81 | R27.2 35.56,36.58 35.56,35.81 | 23.62,49.02 24.13,49.53 v43.31,49.53
  Top 1.016: 23.62,49.02 CON4.8
  Bottom 0.254: v42.93,24.51 43.81,25.4 v43.81,35.81 43.81,41.91 44.2,42.29 44.2,44.58 43.31,45.47 v43.31,49.53
  Bottom 1.27: CON4.8 22.86,49.78 U$13.D14
D15(A0)
  Top 0.254: U1.8 49.91,6.98 50.8,6.1
  Top 1.27: CON2.1 50.8,6.1
  Bottom 1.778: U$13.A0 CON2.1
D16(A1)
  Top 0.254: U1.9 50.41,8.01 51.56,6.86 52.83,6.86 | 53.34,6.35 53.34,6.86 52.83,6.86 | 52.83,6.86 52.83,6.6
  Top 1.27: CON2.2 53.34,6.35
  Bottom 1.778: U$13.A1 CON2.2
D17(A2)
  Top 0.254: U1.10 50.91,8.27 51.82,7.37 55.12,7.37 55.88,6.6
  Top 1.27: 55.88,6.6 CON2.3
  Bottom 1.778: CON2.3 U$13.A2
D18(A3)
  Top 0.254: U1.11 51.41,8.53 52.07,7.87 57.15,7.87 58.42,6.6
  Top 1.27: 58.42,6.6 CON2.4
  Bottom 1.676: CON2.4 U$13.A3
D19(A4)
  Top 0.254: U1.24 60.19,26.42 60.71,25.91 60.71,17.14 61.72,16.13 61.72,8.76 60.96,8
  Top 1.27: CON2.5 60.96,8
  Bottom 1.676: U$13.A4 CON2.5
D20(A5)
  Top 0.254: U1.25 60.46,26.92 61.21,26.16 61.21,17.4 62.23,16.38 62.23,9.27 63.12,8.38
  Top 1.016: CON2.6 63.12,5.46 63.12,8.38
  Bottom 1.778: U$13.A5 CON2.6
D21(CAN_CTRL)  (via drill 0.6)
  Top 0.254: U1.2 46.91,21.66 46.48,22.1 v45.59,22.1
  Top 0.508: v41.91,29.59 40.64,28.32 R25.1
  Bottom 0.254: v45.59,22.1 43.43,22.1 42.04,23.5 42.04,29.46 v41.91,29.59
D22
  Top 0.254: U1.3 47.41,19.86 47.24,19.68 43.31,19.68 42.04,20.95 Q2.2
  Top 0.508: Q2.2 40.13,20.95 C11.1
D23
  Top 0.254: U1.4 47.91,19.47 47.62,19.18 43.69,19.18 43.31,18.8 43.31,18.41
  Top 0.508: 42.93,18.41 43.31,18.41 D23_E.1 | Q2.1 40.13,18.41 C12.1
  Top 1.27: Q2.1 42.93,18.41
D23_EXT  (via drill 0.6)
  Top 0.381: 49.4,0.64 49.47,0.57 61.66,0.57 v62.23,1.14
  Top 0.508: 44.32,18.29 D23_E.2 | 49.4,0.64 48.64,1.4 v48.64,2.16
  Top 1.016: v45.85,18.29 44.32,18.29
  Bottom 0.254: v62.23,1.14 62.23,6.22
  Bottom 0.508: v48.64,2.16 48.64,4.83 45.59,7.87 45.59,16.51 45.85,16.76 v45.85,18.29 | 62.23,6.22 62.23,8.89 64.64,11.3
  Bottom 1.27: 64.64,11.3 EXT.1
D24(CANTX)  (via drill 0.6)
  Top 0.254: U1.62 45.55,23.92 v45.59,23.88 | v47.37,2.16 47.37,2.79 47.75,3.17 49.15,3.17 49.53,2.79 49.53,1.52 49.78,1.27 59.44,1.27 v59.69,1.52 | v45.09,34.67 44.58,34.16 43.31,34.16 42.93,34.54 39.24,34.54 R26.2 | U4.1 36.2,34.92 36.58,34.92
  Top 1.016: R26.2 36.58,34.92
  Bottom 0.254: v47.37,2.16 47.37,5.21 44.96,7.62 44.96,18.67 46.48,20.19 46.48,22.99 v45.59,23.88 44.7,24.77 44.7,31.5 45.09,31.88 v45.09,34.67 | v59.69,1.52 59.69,6.22
  Bottom 0.508: 59.69,6.22 59.69,8.89 62.1,11.3
  Bottom 1.27: 62.1,11.3 EXT.2
D25(MMC_CS)  (via drill 0.6)
  Top 0.254: v53.98,26.8 53.98,27.43 52.83,28.57 51.31,28.57 50.8,28.07 49.78,28.07 49.15,28.7 45.85,28.7 45.06,27.92 U1.54 43.16,27.92 41.66,26.42 36.96,26.42 v34.67,24.13 | v53.98,23.24 54.36,22.86 54.74,22.86 56.01,21.59 58.67,21.59 60.2,20.07 60.2,16.89 61.21,15.88 61.21,14.35 v60.83,13.97
  Top 1.016: R15.2 v10.29,39.75
  Bottom 0.254: v53.98,26.8 v53.98,23.24 | v60.83,13.97 64.24,13.97 | 64.24,13.97 64.39,13.97 | 64.39,13.97 65.15,13.97 65.15,14.35 | v34.67,24.13 35.05,24.51 35.05,34.29 37.85,37.08 37.85,43.94 35.81,45.97 30.48,45.97 29.46,44.96 19.18,44.96 16.52,42.3 SD/MMC.2 15.25,42.3 13.59,40.64 11.18,40.64 v10.29,39.75 | 64.39,13.97 64.77,14.35 | 64.24,13.97 64.75,14.48
  Bottom 1.016: 65.15,14.35 EXT.3
D26  (via drill 0.6)
  Top 0.254: U1.51 49.7,29.42 v50.16,28.96 | v50.16,22.73 50.55,22.35 54.48,22.35 55.75,21.08 58.29,21.08 59.69,19.68 59.69,16 v60.33,15.37
  Bottom 0.254: v50.16,22.73 v50.16,28.96
  Bottom 1.016: v60.33,15.37 60.45,15.24 EXT.4
D27  (via drill 0.6)
  Top 0.254: U1.26 60.72,27.42 61.72,26.42 61.72,17.65 62.87,16.51 64.77,16.51
  Top 1.016: EXT.5 64.77,16.51 | R34.1 R35.1 C32.2 v60.45,12.45
  Bottom 0.254: 59.44,13.46 59.44,15.75 60.2,16.51 64.77,16.51
  Bottom 1.016: v60.45,12.45 59.44,13.46 | 64.77,16.51 EXT.5
D28  (via drill 0.6)
  Top 0.254: U1.27 60.98,27.92 62.23,26.67 62.23,19.05 62.74,18.54
  Top 1.016: EXT.6 62.74,18.54 | R35.2 57.91,14.22 | 57.91,14.22 C32.1 | 57.91,14.22 58.55,14.22 v58.55,15.24
  Bottom 0.508: v58.55,15.24 58.55,15.75 60.58,17.78 62.36,17.78
  Bottom 1.016: 62.36,17.78 EXT.6
D29(SCL2)  (via drill 0.6)
  Top 0.254: U1.29 58.66,28.92 59.46,29.72 60.33,29.72 60.71,29.34 60.71,28.96 62.99,26.67 64.26,26.67 64.77,26.16 64.77,21.59 | v31.88,20.19 32.11,20.19 33.25,21.34 34.73,21.34 v35.05,21.65 | v35.94,9.27 36.32,9.65 47.75,9.65 48.9,8.51 v48.9,6.86
  Top 0.508: UEXT.5 11.43,27.3 12.7,27.3 R8.1
  Top 1.016: EXT.7 64.77,21.59
  Bottom 0.254: 9.53,25.4 9.53,8.13 9.78,7.87 16.13,7.87 17.53,9.27 17.53,10.92 17.91,11.3 19.05,11.3 21.08,9.27 22.1,9.27 23.5,7.87 27.43,7.87 28.83,9.27 28.83,13.72 31.88,16.76 31.88,17.78 32.13,18.03 32.13,19.94 v31.88,20.19 | v35.05,21.65 35.31,21.4 35.31,9.91 v35.94,9.27 | v48.9,6.86 48.9,7.37 56.64,15.11 57.02,15.11 60.96,19.05 64.77,19.05 65.15,19.43
  Bottom 1.016: 9.53,25.4 UEXT.5 | 65.15,19.43 EXT.7
D30(SDA2)  (via drill 0.6)
  Top 0.254: 9.53,27.94 11.43,27.94 12.32,28.83 12.7,28.83 R9.1 | U1.30 58.45,29.42 59.26,30.23 60.71,30.23 v61.59,29.34
  Top 1.016: UEXT.6 9.53,27.94
  Bottom 0.254: 64.77,21.59 64.77,23.62 64.26,24.13 62.99,24.13 61.59,25.53 v61.59,29.34 61.59,33.4 62.48,34.29 62.48,44.2 64.77,46.48 64.77,51.82 64.52,52.07 21.72,52.07 21.34,51.69 21.34,49.4 20.45,48.51 18.29,48.51 14.48,52.32 6.86,52.32 5.91,51.37 2.6,51.37 1.12,49.89 1.12,32.28 6.73,26.67
  Bottom 1.016: 64.77,21.59 EXT.8
  Bottom 1.27: 6.73,26.67 UEXT.6
D31(#SS2)
  Top 0.254: U1.33 53.91,33.21 53.98,33.27 55.24,33.27 56.13,34.16 60.63,34.16 62.03,32.77 66.29,32.77 67.82,31.24 67.82,24.64 67.18,24
  Top 1.016: 67.18,24 EXT.9
D32(SCK2)  (via drill 0.6)
  Top 0.254: U1.34 53.41,33.48 53.72,33.78 54.99,33.78 55.88,34.67 61.37,34.67 v61.49,34.54 | v61.34,43.94 59.69,45.59 49.28,45.59 48.13,44.45 40.64,44.45 39.37,43.18 37.97,43.18 37.47,43.69 34.16,43.69 v34.04,43.81
  Bottom 0.254: 61.85,22.86 60.71,24 60.71,33.76 v61.49,34.54 61.72,34.77 61.72,42.29 61.34,42.67 v61.34,43.94 | v34.04,43.81 34.04,44.07 33.27,44.83 31.62,44.83 28.57,41.78 23.75,41.78 22.35,43.18 20.22,43.18 17.91,40.87 17.91,39.75 17.15,39
  Bottom 0.508: SD/MMC.5 17.15,39
  Bottom 1.016: 61.85,22.86 EXT.10
D33(MISO2)  (via drill 0.6)
  Top 0.254: U1.35 52.91,31.87 53.16,31.62 54.48,31.62 v55.24,32.38 56.52,33.66 60.43,33.66 61.82,32.26 66.04,32.26 67.31,30.99 67.31,26.67 66.8,26.16 | v54.74,44.32 53.98,45.09 49.53,45.09 48.39,43.94 40.89,43.94 39.62,42.67 37.72,42.67 37.21,43.18 34.8,43.18 34.54,42.93 33.4,42.93 32.77,43.56 v32.77,43.81
  Top 0.508: R13.2 11.68,37.08 v12.32,37.08
  Top 1.016: 66.8,26.16 EXT.11
  Bottom 0.254: v55.24,32.38 55.24,33.78 55.63,34.16 55.63,43.43 v54.74,44.32 | v32.77,43.81 31.37,43.81 28.83,41.27 26.29,41.27 24.64,39.62 23.77,39.62 22.12,41.27 20.45,41.27 19.43,40.26 19.43,37.85 18.41,36.83 17.27,36.83 | 14.86,36.83 12.57,36.83 v12.32,37.08
  Bottom 0.508: 14.86,36.83 15.85,36.83 SD/MMC.7 15.92,36.83 17.27,36.83
D34(MOSI2)  (via drill 0.6)
  Top 0.254: U1.36 52.41,33.39 53.31,34.29 54.71,34.29 55.6,35.18 60.83,35.18 61.09,35.43 62.1,35.43 63.12,34.42 v63.12,33.66 | v63.5,43.43 60.83,46.1 49.02,46.1 47.88,44.96 40.39,44.96 39.12,43.69 38.23,43.69 37.72,44.2 34.92,44.2 34.42,44.7 26.8,44.7 v26.16,44.07
  Top 1.016: R14.2 11.56,38.48 v12.29,38.48
  Bottom 0.254: 62.87,26.04 62.23,26.67 62.23,28.7 62.48,28.96 62.48,29.72 62.23,29.97 62.23,32.77 v63.12,33.66 63.12,41.91 63.5,42.29 v63.5,43.43 | v26.16,44.07 25.27,44.07 24.89,44.45 19.71,44.45 16.46,41.2 SD/MMC.3 15.29,41.2 14.22,40.13 13.59,40.13 12.29,38.84 v12.29,38.48
  Bottom 1.016: 62.87,26.04 EXT.12
D35  (via drill 0.6)
  Top 0.254: U1.37 51.91,33.63 53.09,34.8 54.48,34.8 55.37,35.69 60.58,35.69 60.83,35.94 62.36,35.94 64.01,34.29 64.01,33.66 64.39,33.27 65.66,33.27 v66.17,33.78
  Bottom 0.254: v66.17,33.78 67.31,32.64 67.31,29.21 66.67,28.57
  Bottom 1.016: 66.67,28.57 EXT.13
D36  (via drill 0.6)
  Top 0.254: U1.38 51.41,33.89 52.83,35.31 54.23,35.31 55.12,36.2 60.33,36.2 60.58,36.45 62.61,36.45 v64.9,34.16
  Bottom 0.254: v64.9,34.16 64.77,34.04 64.77,29.21
  Bottom 1.016: 64.77,29.21 EXT.14
D37
  Top 0.254: U1.39 50.91,31.64 51.05,31.5 52.58,31.5 52.96,31.11 55.63,31.11 57.66,33.15 60.2,33.15 61.59,31.75 64.77,31.75 65.28,31.24
  Top 1.016: 65.28,31.24 EXT.15
D+
  Top 0.305: 8.89,43.31 9.25,42.95 10.68,42.95 10.79,43.06 U6.6 U6.1 13.33,43.06 13.84,42.55 15.62,42.55 R4.2
  Top 0.508: USB.D+ 8.89,43.31
D-
  Top 0.305: 8.8,44.11 9.53,44.83 10.54,44.83 10.92,44.45 10.92,44.2 11.06,44.06 U6.4 U6.3 13.33,44.06 13.84,44.58 15.62,44.58 R3.2
  Top 0.508: USB.D- 8.8,44.11
DISC  (via drill 0.6)
  Top 0.254: U1.53 42.9,28.42 41.4,26.92 35.81,26.92 v34.16,25.27 | v11.94,34.42 12.57,35.05 14.61,35.05 14.86,35.3 14.86,36.83 13.78,37.91 T1.1
  Bottom 0.254: v11.94,34.42 13.72,34.42 14.1,34.04 14.1,32.64 14.35,32.38 16.64,32.38 19.94,35.69 19.94,40.01 20.7,40.77 21.92,40.77 23.57,39.12 24.92,39.12 26.57,40.77 29.21,40.77 31.37,42.93 35.81,42.93 36.83,41.91 36.83,37.59 34.04,34.8 34.04,27.81 33.27,27.05 33.27,26.16 v34.16,25.27
GND  (via drill 0.6)
  Top 0.254: C12.2 37.85,17.78 38.99,16.64 40.89,16.64 41.66,17.4 46.99,17.4 47.88,18.29 | U1.63 42.62,23.42 42.04,24 42.04,24.89 41.66,25.27 40.77,25.27 40.13,24.64 39.37,24.64 37.85,23.11 C6.1 | U1.18 58.85,23.42 C5.1 | C3.1 59.44,30.99 59.31,30.99 58.24,29.92 U1.31 | U1.28 59.41,28.42 v59.82,28.83 | C4.1 41.53,33.66 46.74,33.66 46.91,33.48 U1.47 | LED1.C 12.45,52.2 13.97,50.67 13.97,49.15 14.1,49.02 15.62,49.02 15.75,48.9 15.75,51.31 LED2.C
  Top 0.305: v14.22,43.56 U6.2
  Top 0.508: R21.1 22.73,10.79 v22.73,12.7 | v34.04,14.1 34.54,13.59 34.54,11.43 34.92,11.05 35.28,11.05 | 47.95,11.05 48.26,11.05 48.77,11.56 48.77,14.86 48.13,15.49 C14.2 | 60.45,39.12 SWD.3 | 60.2,39.12 60.45,39.12 | 60.45,39.12 SWD.5 | U4.2 34.92,35.31 34.16,36.07 34.16,36.7 C23.2 | USB.GND 8.69,41.71 9.27,42.29 12.32,42.29 13.08,41.53 | R31.2 52.7,42.42 52.96,42.42 53.85,43.31 v59.82,43.31 | 15.75,48.9 16.51,48.9 17.78,47.62 18.54,47.62 19.3,46.86 25.4,46.86 25.4,46.99 27.05,45.34 34.8,45.34 35.31,44.83 38.48,44.83 v38.73,44.58
  Top 0.61: 24.26,26.04 U2.4 | 24.26,26.04 25.65,26.04 C18.2 | C21.2 19.68,11.68 20.57,12.57 22.61,12.57 v22.73,12.7 22.86,12.57 U3.2 24.77,12.57 25.65,11.68 C22.2 | 24.26,26.42 24.26,26.04 | 59.82,42.55 59.82,42.29 SWD.9
  Top 0.66: v25.91,19.43 26.54,18.8 v30.1,18.8
  Top 0.762: v18.54,10.29 18.54,7.11 | EXT.16 61.67,30.48 60.78,31.37 C3.1 | v29.46,39.24 29.34,39.12 26.67,39.12 26.54,39.24 C15.2
  Top 0.889: v18.54,10.29 18.54,11.56
  Top 1.016: C21.2 19.56,11.56 18.54,11.56 C20.2 | C31.2 18.54,7.11 R29.1 29.59,7.11 29.94,6.76 29.94,6.73 | 24.26,26.42 R19.2 24.64,28.07 26.42,28.07 v26.67,28.32 27.81,28.32 | v25.91,19.43 C19.- | 29.94,6.73 CAN.1 | 37.85,19.68 C12.2 | 37.85,19.68 C11.2 C6.1 | 37.85,19.68 Q2.GND 34.04,18.92 | 35.43,15.49 C13.2 | 35.43,15.49 35.43,17.27 34.04,18.67 34.04,18.92 | U5.3 34.04,14.05 v34.04,14.1 35.43,15.49 | 47.95,11.05 v42.67,11.05 35.28,11.05 | 29.94,6.73 43.05,6.73 | 43.05,6.73 43.18,6.73 CON1.5 | v59.82,25.53 C5.1 | v59.82,32.26 C3.1 | v59.82,39.12 60.2,39.12 60.83,39.12 | 60.83,39.12 60.83,38.73 | 60.83,39.12 60.83,39.5 | v59.82,43.31 59.82,42.55 | 34.04,18.92 30.23,18.92 v30.1,18.8 | 43.05,6.73 46.99,6.73 v47.88,7.62 | C7.2 13.08,41.53 v12.57,42.04 | 12.83,45.85 C8.1 | v12.83,45.09 12.83,45.85 | 12.83,45.85 C9.2 | R22.1 C25.2 v27.18,32.26 26.16,32.26 C26.2 25.78,32.38 24.64,33.53 19.63,33.53 VR1.1 19.36,33.53 18.92,33.53 18.54,33.91 18.16,33.91 C24.2 | v38.73,37.97 33.91,37.97 | 33.91,37.97 C23.2 | v37.72,33.4 R24.1 41.53,33.4 C4.1 | C7.2 R15.1 13.59,39.24 v14.22,39.24 | R2.2 23.88,40.77 v24.13,40.51 26.54,40.51 | v39.88,19.68 37.85,19.68 | 33.91,37.97 v32.64,37.97 | 28.45,28.32 D2.A | 29.08,28.32 28.45,28.32 | 29.08,28.32 v29.84,28.32 | 27.81,28.32 28.45,28.32 | 27.81,28.32 v27.81,27.18 28.45,27.18 | 29.08,28.32 v29.08,27.18 28.45,27.18 | 28.45,27.18 28.45,28.32 | C15.2 26.54,40.51 | 26.54,40.51 C33.2 | C7.2 C10.2
  Top 1.27: 2.79,8.64 X1.2 2.92,8.68 2.92,2.79 3.54,2.17 LIPO_BAT.2 | PWR_LED.C 13.21,7.11 12.7,6.6 8.76,6.6 PWR_J.-- | v5.59,18.67 C17.2 C16.- | 25.4,46.99 CON4.7
  Top 1.778: 5.57,8.64 5.57,11.05 | 2.79,8.64 5.57,8.64 | 5.57,8.64 5.57,8.15 7.11,6.6 8.76,6.6 | 5.57,12.5 PWR_J.- 5.57,11.05 | 5.57,11.05 5.59,11.05
  Bottom 0.254: v58.8,9.91 52.32,9.91 49.78,7.37 49.78,6.48 49.28,5.97 48.39,5.97 47.88,6.48 v47.88,7.62
  Bottom 0.508: 27.43,18.8 27.43,19.05
  Bottom 0.66: v25.91,19.43 26.54,18.8 27.43,18.8 v30.1,18.8
  Bottom 0.762: v24.13,40.51 23.95,40.51 22.17,42.29 20.4,42.29 18.67,40.56 18.67,38.35 18.21,37.9 SD/MMC.6 14.81,37.9 14.22,38.48 v14.22,39.24
  Bottom 1.016: v59.82,43.31 v59.82,39.12 60.71,38.23 60.71,35.56 59.82,34.67 v59.82,32.26 v59.82,28.83 v59.82,25.53 59.82,19.18 56.64,16 56.26,16 v47.88,7.62 | CON1.5 42.67,5.59 v42.67,11.05 42.67,16.89 v39.88,19.68 39.88,23.62 38.48,25.02 38.48,33.4 v37.72,33.4 38.35,33.4 38.73,33.78 v38.73,37.97 v38.73,44.58 | v12.83,45.09 12.83,43.56 v14.22,43.56 12.57,43.56 v12.57,42.04 | 27.18,29.46 27.18,28.83 v26.67,28.32 25.91,27.56 v25.91,19.43 C19.- | 27.18,29.46 v27.18,32.26 27.18,38.23 28.19,39.24 v29.46,39.24 | v32.64,37.97 30.86,36.2 30.86,30.99 29.84,29.97 29.84,29.46 | 29.84,29.46 v29.84,28.32 29.84,27.94 v29.08,27.18 29.08,26.29 27.43,24.64 27.43,19.05 | 27.18,29.46 29.84,29.46
  Bottom 1.27: v5.59,18.67 5.59,18.92 | 5.59,11.3 5.57,11.3 | 18.54,8.26 v18.54,10.29 | CON4.7 25.4,49.78 U$13.GND@1 | CAN.1 29.94,5.94 31.5,7.49 31.5,11.56 v34.04,14.1
  Bottom 1.778: 5.59,18.92 UEXT.2 | 5.59,11.05 5.59,11.3 | 5.59,11.05 v5.59,18.67 | CON1.5 U$13.GND | 4.06,11.05 5.59,11.05 | 5.59,11.05 7.24,11.05 | 18.54,8.26 16.89,6.6 8.89,6.6 | PWR_J.-- 8.81,6.6 8.89,6.6 | 7.11,6.6 5.57,8.15 | 5.57,8.64 5.57,8.13 | 5.57,8.64 5.57,10.54 | 8.89,6.6 7.24,6.6 | 5.57,8.64 5.59,8.64 | 2.67,8.64 5.57,8.64
  other vias: 64.26,40.89 58.42,17.78 48.26,14.1
  pour Bottom (isolate 0.381, rank 2): -4.19,57.78 71.37,57.78 71.37,-6.48 -4.19,-6.48
  pour Top (isolate 0.406, rank 2): -3.43,57.15 70.87,57.15 70.87,-4.57 -3.43,-4.57
MCIDAT1  (via drill 0.6)
  Top 0.762: v7.75,34.67 8.64,34.67 R12.2
  Bottom 0.254: 14.86,35.69 11.68,35.69 10.67,34.67 v7.75,34.67
  Bottom 0.508: SD/MMC.8 15.87,35.69 14.86,35.69
MCIDAT2  (via drill 0.6)
  Top 0.508: v6.6,36.52 6.6,34.16 7.37,33.4 R11.2
  Bottom 0.254: v6.6,36.52 6.6,36.58 6.73,36.58 7.75,35.56 9.14,35.56 9.4,35.81 9.4,40.26 10.29,41.15 13.06,41.15 15.31,43.4 SD/MMC.1
MMC_PWR  (via drill 0.6)
  Top 1.016: 28.32,41.4 C15.1 | v28.32,42.8 C33.1 28.32,41.4 | 28.32,41.4 L3.2
  Bottom 0.508: v28.32,42.8 28.07,42.55 23.88,42.55 22.61,43.81 19.96,43.81 17.27,41.12 17.27,40.51 16.89,40.13 16.76,40.13 16.73,40.1 SD/MMC.4
N$1
  Top 0.254: R23.2 30.99,23.75
  Top 0.508: 30.99,23.75 CAN_T.1
N$2
  Top 0.254: LED1_E.1 13.08,47.75 12.95,47.88 12.95,49.15 11.94,50.16 R6.2
N$3
  Top 0.508: R25.2 38.86,29.84 36.2,29.84 U4.8
  Top 1.016: R25.2 R24.2
N$4
  Top 0.508: R10_E.1 15.9,30.35 15.65,30.61
  Top 1.016: 15.65,30.61 14.99,30.61 R10.2
N$5
  Top 1.016: R7.1 LED2.A
N$6
  Top 0.508: LED2_E.1 19.18,48.39 18.16,48.39 R7.2
N$7
  Top 1.016: D3.A 17.91,20.32 21.34,16.89 C19.+ 22.48,17.27 29.19,17.27 L1.2
N$8
  Top 1.016: PWR_LED.A 13.97,5.08 R20.2
N$11
  Top 0.254: 16.13,1.14 16.76,0.51 20.45,0.51 21.21,1.27 21.21,4.19 20.83,4.19
  Top 1.016: RST.1_1 16.13,1.14 | 20.83,4.19 19.94,5.08 R29.2
N$12
  Top 0.254: BUT.1_1 3.05,51.82 5.46,51.82 6.1,51.18 6.1,49.91 6.22,49.78 8.76,49.78 9.53,49.02 11.18,49.02 R30.2
N$13
  Top 1.27: D1.A 14.61,9.91 12.83,9.91 12.06,10.67 12.06,11.05 PWR_J.+ 12.06,13.59
  Top 1.778: X1.1 3.85,14.73 10.92,14.73 12.06,13.59
N$22
  Top 0.559: U3.5 21.72,11.62 21.72,11.3
  Top 1.016: R21.2 21.72,11.3
N$23
  Top 1.016: R6.1 10.03,51.82 LED1.A
N$33
  Top 0.61: U2.3 C18.1
N$34  (via drill 0.6)
  Top 0.762: VR2.P$2 arc2 VR2.2 17.65,36.58 C29.1 | C29.1 17.91,36.45 | C24.1 17.14,32.64 16.51,33.27 16.51,35.31 C29.1
  Top 1.016: 30.23,9.53 D4.K | v27.75,9.53 29.52,9.53 | 29.52,9.53 FET1.2 30.23,11.15 30.23,9.53 | VR1.P$2 VR1.2 18.41,31.75 v18.16,31.5 18.16,31.75 17.65,32.26 C24.1 | 29.52,9.53 30.23,9.53 | 29.52,9.53 29.08,9.53
  Bottom 1.016: v27.75,9.53 26.98,8.76 24.13,8.76 22.73,10.16 21.46,10.16 17.91,13.72 17.91,30.73 18.16,30.99 v18.16,31.5
N$41
  Top 0.254: U1.5 48.41,18.06 47.24,16.89 42.04,16.89 40.77,15.62 R32.2
  Top 1.016: Q1.2 38.73,12.32 C13.1 R32.2
N$42
  Top 0.254: U1.6 48.91,17.8 47.5,16.38 45.34,16.38 44.58,15.62 C14.1
  Top 1.016: R32.1 C14.1 44.58,12.32 Q1.1
N$56
  Top 0.508: T1.3 16.51,36.96 16.51,38.86 R5.2
N$61
  Top 0.61: U2.5 20.45,26.04 20.95,26.54 R18.2
  Top 1.016: R18.2 R19.1
N$64  (via drill 0.6)
  Top 0.61: 18.48,22.73 U2.8 U2.1 | 18.1,22.73 18.48,22.73 | 18.48,22.73 U2.7
  Top 1.016: R17.2 14.99,25.91 v16.51,25.91 | v16.64,22.73 18.1,22.73
  Top 1.27: R17.2 R16.2
  Bottom 1.016: v16.64,22.73 16.51,22.86 v16.51,25.91
N$67
  Top 0.61: 28.45,23.5 D2.K
  Top 1.016: U2.2 28.45,23.5
  Top 1.27: 28.45,23.5 28.45,21.06 L1.1
N$76  (via drill 0.6)
  Top 0.254: R23.1 30.99,26.67 31.11,26.67
  Top 0.508: U4.6 33.66,28.19 32.77,27.3 31.11,27.3
  Top 1.016: v31.11,27.94 31.11,27.3 31.11,26.67
  Bottom 0.254: 27.18,5.97 29.84,8.64 29.84,13.31 32.89,16.36 32.89,17.27 33.27,17.65 33.27,20.78 31.75,22.3 31.75,27.3 v31.11,27.94
  Bottom 1.016: CAN.2 26.44,5.24 27.18,5.97
N$77  (via drill 0.6)
  Top 0.254: U4.7 34.92,28.07 34.42,27.56 33.91,27.56 33.02,26.67 33.02,25.78 | 33.02,24.64 33.15,24.64 33.4,24.38 33.66,24.38 33.78,24.26 33.78,23.3 33.47,22.99 32.64,22.99 32.13,22.48 30.23,22.48 v29.84,22.1
  Top 0.508: 33.02,24.64 CAN_T.2
  Top 0.762: 33.02,24.64 33.02,25.78
  Bottom 0.254: 25.24,6.86 25.75,7.37 27.69,7.37 29.34,9.02 29.34,13.51 32.38,16.56 32.38,17.53 32.77,17.91 32.77,20.57 31.24,22.1 v29.84,22.1
  Bottom 1.016: CAN.3 25.24,6.86
N$82
  Top 0.254: U1.40 50.41,34.16 R33.2
PIN3_VOLTAGE
  Bottom 0.762: CON1.3 3V3A/5V.2
  Bottom 1.778: U$13.5V CON1.3
RESET  (via drill 0.6)
  Top 0.254: C31.1 18.41,5.46 19.18,6.22 20.83,6.22 v21.21,5.84 | 33.02,9.78 34.04,9.78 34.42,10.16 48.51,10.16 49.41,11.06 U1.7 49.41,21.6 49.66,21.84 54.23,21.84 54.86,21.21 v54.86,20.45 | v54.36,42.29 54.13,42.29 | 53.49,41.66 53.11,41.27 51.56,41.27 50.16,39.88
  Top 0.508: v21.21,8.38 21.46,8.13 32.89,8.13 v33.02,8 33.02,9.78 31.56,11.24 U5.1 | 54.13,42.29 53.49,41.66 | 50.16,39.88 R-T.2
  Top 0.61: v54.36,42.29 SWD.10
  Top 1.016: C31.1 R28.2 16.64,4.06 15.24,2.67 RST.2_1 | v21.21,8.38 20.45,9.14 D6.A
  Bottom 0.254: v54.86,20.45 54.86,23.62 55.63,24.38 55.63,30.73 54.36,32 54.36,33.66 55.12,34.42 55.12,41.53 v54.36,42.29
  Bottom 1.016: v21.21,5.84 v21.21,8.38 | v33.02,8 CON1.1
  Bottom 1.778: CON1.1 U$13.RST
TCK/SWCLK  (via drill 0.6)
  Top 0.254: U1.49 52.23,30.42 53.7,28.96 v53.72,28.96
  Top 0.66: v53.72,38.48 SWD.4
  Bottom 0.254: v53.72,28.96 53.34,29.34 53.34,38.1 v53.72,38.48
TDI  (via drill 0.6)
  Top 0.254: U1.50 51.49,29.92 v51.94,29.46
  Top 0.66: v54.23,40.89 54.36,41.02 SWD.8
  Bottom 0.254: v51.94,29.46 52.32,29.84 52.32,39.88 53.34,40.89 v54.23,40.89
TDO/SWO  (via drill 0.6)
  Top 0.254: U1.55 45.33,27.42 46.1,28.19 48.91,28.19 49.8,27.3 v52.83,27.3
  Top 0.66: v53.72,39.75 SWD.6
  Bottom 0.254: v52.83,27.3 52.83,38.99 53.59,39.75 v53.72,39.75
TMS/SWDIO  (via drill 0.6)
  Top 0.254: U1.46 47.41,31.45 47.88,30.99 52.38,30.99 53.14,30.23 v54.23,30.23
  Top 0.66: v54.23,37.34 54.36,37.21 SWD.2
  Bottom 0.254: v54.23,30.23 54.23,31.24 53.85,31.62 53.85,33.91 54.23,34.29 v54.23,37.34
TRST  (via drill 0.6)
  Top 0.254: U1.56 v46.1,26.92
  Top 0.508: v45.21,40.39 45.72,39.88 R-T.1
  Bottom 0.254: v46.1,26.92 46.1,31.11 46.48,31.5 46.48,35.43 45.21,36.7 v45.21,40.39
UEXT_#CS
  Top 0.254: 9.53,30.48 12.83,30.48 R10.1 14.35,32 D10/D4.2
  Top 1.016: UEXT.10 9.53,30.48
USB_P  (via drill 0.6)
  Top 0.254: U1.52 42.64,28.92 41.15,27.43 35.05,27.43 v34.16,26.54
  Top 0.508: v24.28,43.56 21.72,43.56
  Top 1.016: R2.1 21.72,43.56 R1.2
  Bottom 0.254: 24.89,43.56 25.27,43.18 26.54,43.18 27.81,44.45 29.72,44.45 30.73,45.47 35.56,45.47 37.34,43.69 37.34,37.34 34.54,34.54 34.54,26.92 v34.16,26.54
  Bottom 0.508: 24.89,43.56 v24.28,43.56
USB_SHIELD
  Top 1.016: USB.GND2 USB.GND1 2.41,48.26 2.41,38.36 USB.GND3 USB.GND4 8.13,38.36 8.13,39.62 9.78,41.27 C7.1
USBDM
  Top 0.254: U1.44 48.41,36.93 47.88,37.47 45.21,37.47 42.04,40.64 36.58,40.64 36.32,40.39 35.43,40.39 35.18,40.64 32.89,40.64 32.64,40.89 32.64,42.55 30.99,44.2 27.56,44.2 26.54,43.18 25.65,43.18 25.27,43.56 25.27,44.07 24.38,44.96 21.06,44.96 20.42,44.32 R3.1
  Top 1.016: R3.1 C9.1
USBDP
  Top 0.254: U1.45 47.91,36.67 47.62,36.96 44.96,36.96 41.78,40.13 36.83,40.13 36.58,39.88 35.18,39.88 34.92,40.13 32.64,40.13 32.13,40.64 32.13,42.29 30.73,43.69 27.81,43.69 26.8,42.67 23.11,42.67 22.73,42.29 22.73,41.91 22.48,41.66 20.8,41.66 19.66,42.8 R4.1
  Top 1.016: R4.1 C10.1 R5.1
VBAT  (via drill 0.6)
  Top 0.254: R34.2 55.37,13.34 55.37,11.43 59.69,7.11 59.69,4.32 59.18,3.81 31.88,3.81 30.48,2.41 v28.19,2.41
  Top 0.61: U3.3 25.78,13.52 C22.1
  Top 1.016: 28.57,13.46 FET1.3 | 28.57,13.46 C22.1 | v31.24,13.46 28.57,13.46
  Bottom 0.254: 15.24,2.03 16.76,0.51 26.29,0.51 v28.19,2.41 28.19,5.84 30.35,8 30.35,12.06 31.24,12.95 v31.24,13.46
  Bottom 1.016: LIPO_BAT.1 5.48,4.17 7.62,2.03 15.24,2.03
VCC  (via drill 0.6)
  Top 0.254: U1.1 46.41,20.19 44.2,20.19 43.31,21.08 43.31,22.61 43.18,22.73 43.37,22.92 U1.64 | U1.19 57.58,23.92 C5.2 | C4.2 44.07,33.15 46.35,33.15 46.41,33.09 U1.48 | U6.5 10.34,43.56 v10.03,43.87 | U1.32 57.09,30.42 C3.2
  Top 0.508: D6.C 16.59,8.51 12.95,8.51 12.57,8.13 11.05,8.13 v10.41,8.76 | v41.15,24.38 41.15,22.86 41.27,22.73 43.18,22.73 | v40.64,36.7 40.64,36.96 | C4.2 43.31,32.13 42.16,30.99 v40.64,30.99 | 17.27,30.23 17.27,30.35 R10_E.2 | T1.2 13.44,35.69 11.43,35.69 R12.1
  Top 0.66: v59.18,37.08 59.31,37.21 SWD.1
  Top 0.762: v10.03,45.85 C8.2 | 37.21,39.24 37.08,39.12 34.04,39.12 v33.91,39.24 | R11.1 10.79,33.27 11.43,33.27 v12.7,32
  Top 1.016: D6.C 16.64,9.1 R28.1 | U5.2 33.46,10.86 v33.66,10.67 | v41.15,24.38 41.15,22.99 C6.2 | v40.64,36.7 R26.1 R27.1 | v58.55,25.53 58.55,24.89 C5.2 | v58.55,32.26 58.55,31.88 C3.2 | v34.92,8 v44.07,8 46.35,8 v47.12,8.76 | R11.1 R12.1 10.67,35.26 9.53,36.4 R13.1 | 37.21,39.24 v40.64,39.24 | v33.91,39.24 31.11,39.24 L3.1 | v9.53,47.88 10.03,47.88 R30.1 | v31.11,29.21 31.11,29.61 30.48,30.25 L2.1 30.23,30.48 C25.1 26.16,30.48 C26.1 26.16,30.23 25.4,29.46 20.95,29.46 20.17,30.25 VR1.3 19.33,30.23 17.27,30.23 17.27,29.21 16.51,28.45 v16.26,28.45 14.86,28.45 | 14.86,28.45 R9.2 | 14.86,28.45 R8.2 | R13.1 R14.1 | R13.1 9.53,36.45 v8.51,36.45
  Bottom 0.762: 13.21,28.45 13.21,31.5 v12.7,32
  Bottom 1.016: v10.41,8.76 10.41,21.21 UEXT.1 12.7,23.5 12.7,27.94 13.21,28.45 v16.26,28.45 | 34.92,7.98 v34.92,8 33.66,9.27 v33.66,10.67 | v59.18,37.08 58.55,36.45 v58.55,32.26 v58.55,25.53 58.55,19.68 56.13,17.27 55.63,17.27 v47.12,8.76 | v44.07,8 44.07,20.07 41.15,22.99 v41.15,24.38 41.15,28.45 40.64,28.96 v40.64,30.99 v40.64,36.7 v40.64,39.24 | v9.53,47.88 10.03,47.37 v10.03,45.85 v10.03,43.87 10.03,42.8 8.51,41.27 v8.51,36.45 | v31.11,29.21 32.13,30.23 32.13,35.69 33.91,37.47 v33.91,39.24
  Bottom 1.524: 34.92,7.98 35.43,7.47 35.43,5.21 CON1.2
  Bottom 1.778: CON1.2 U$13.3V3
VDD  (via drill 0.6)
  Top 0.254: U1.13 52.41,18.2 C2.2
  Top 0.762: L2.2 30.46,33.02 31.24,33.02 32.26,32 v35.94,32
  Top 1.016: C2.2 54.48,16.13 C1.2 v54.48,8.76 | L2.2 C27.1 30.23,35.69 C28.1 C30.1 25.4,35.69 24.51,34.8 20.32,34.8 20.04,35.08 VR2.3
  Bottom 0.254: v54.48,8.76 54.48,6.48 54.61,6.35 54.61,1.52 53.85,0.76 40.39,0.76 39.37,1.78 39.37,7.11 39.24,7.24
  Bottom 0.762: 39.12,9.14 39.24,9.02 3V3A/5V.1 39.24,7.24
  Bottom 1.016: 39.12,9.14 39.12,15.75 37.34,17.53 37.34,22.61 35.94,24 v35.94,32

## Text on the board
Top: 258 errors
Bottom: 152 errors
tPlace: 377 errors
tNames: OLIMEXINO-STM32 | Rev.F | 9-30VDC | + | + | https://www.olimex.com | CANH | CANL | GND | JUMPER | STATE | DESCRIPTION | UEXT_#CS is connected to D10 | D10/D4 | UEXT_#CS is connected to D4 | LED1_E is connected to D13 | LED1_E | LED1_E is not connected | LED2_E is connected to D3 | LED2_E | LED2_E is not connected | CAN termination is enabled | CAN_T | CAN termination is disabled | D23 is connected to EXT | D23_E | D23 is not connected to EXT | TRST and RESET are connected | R-T | TRST and RESET are separated
bNames: DIGITAL | CON4 | DIGITAL | CON3 | LED1 | LED2 | D14 | GND | D13 | D12 | D11 | D10 | D9 | D8 | D7 | D6 | D5 | D4 | D3 | D2 | D1 | D0 | DESCRIPTION | STATE | JUMPER | UEXT_#CS is connected to D10 | D10/D4 | UEXT_#CS is connected to D4 | LED1_E is connected to D13 | LED1_E | LED1_E is not connected | LED2_E is connected to D3 | LED2_E is not connected | LED2_E | CAN termination is enabled | CAN_T | CAN termination is disabled | D23 is connected to EXT | D23_E | D23 is not connected to EXT | TRST and RESET are connected | R-T | + | TRST and RESET are separated | Designed by: | - | https://www.olimex.com | PWR_J | + | - | 9-30VDC | A5 | - | RST | 3V3 | GNDA | GND | VIN | A0 | A1 | A2 | A3 | A4 | 5V | + | RST | CANH | CANL | GND | 3.7V | - | LIPO_BAT | POWER | CON1 | ANALOG | CON2
213bmp: POLIGONI NA CIFROVOTO ZAHRANVANE I CHARGERA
